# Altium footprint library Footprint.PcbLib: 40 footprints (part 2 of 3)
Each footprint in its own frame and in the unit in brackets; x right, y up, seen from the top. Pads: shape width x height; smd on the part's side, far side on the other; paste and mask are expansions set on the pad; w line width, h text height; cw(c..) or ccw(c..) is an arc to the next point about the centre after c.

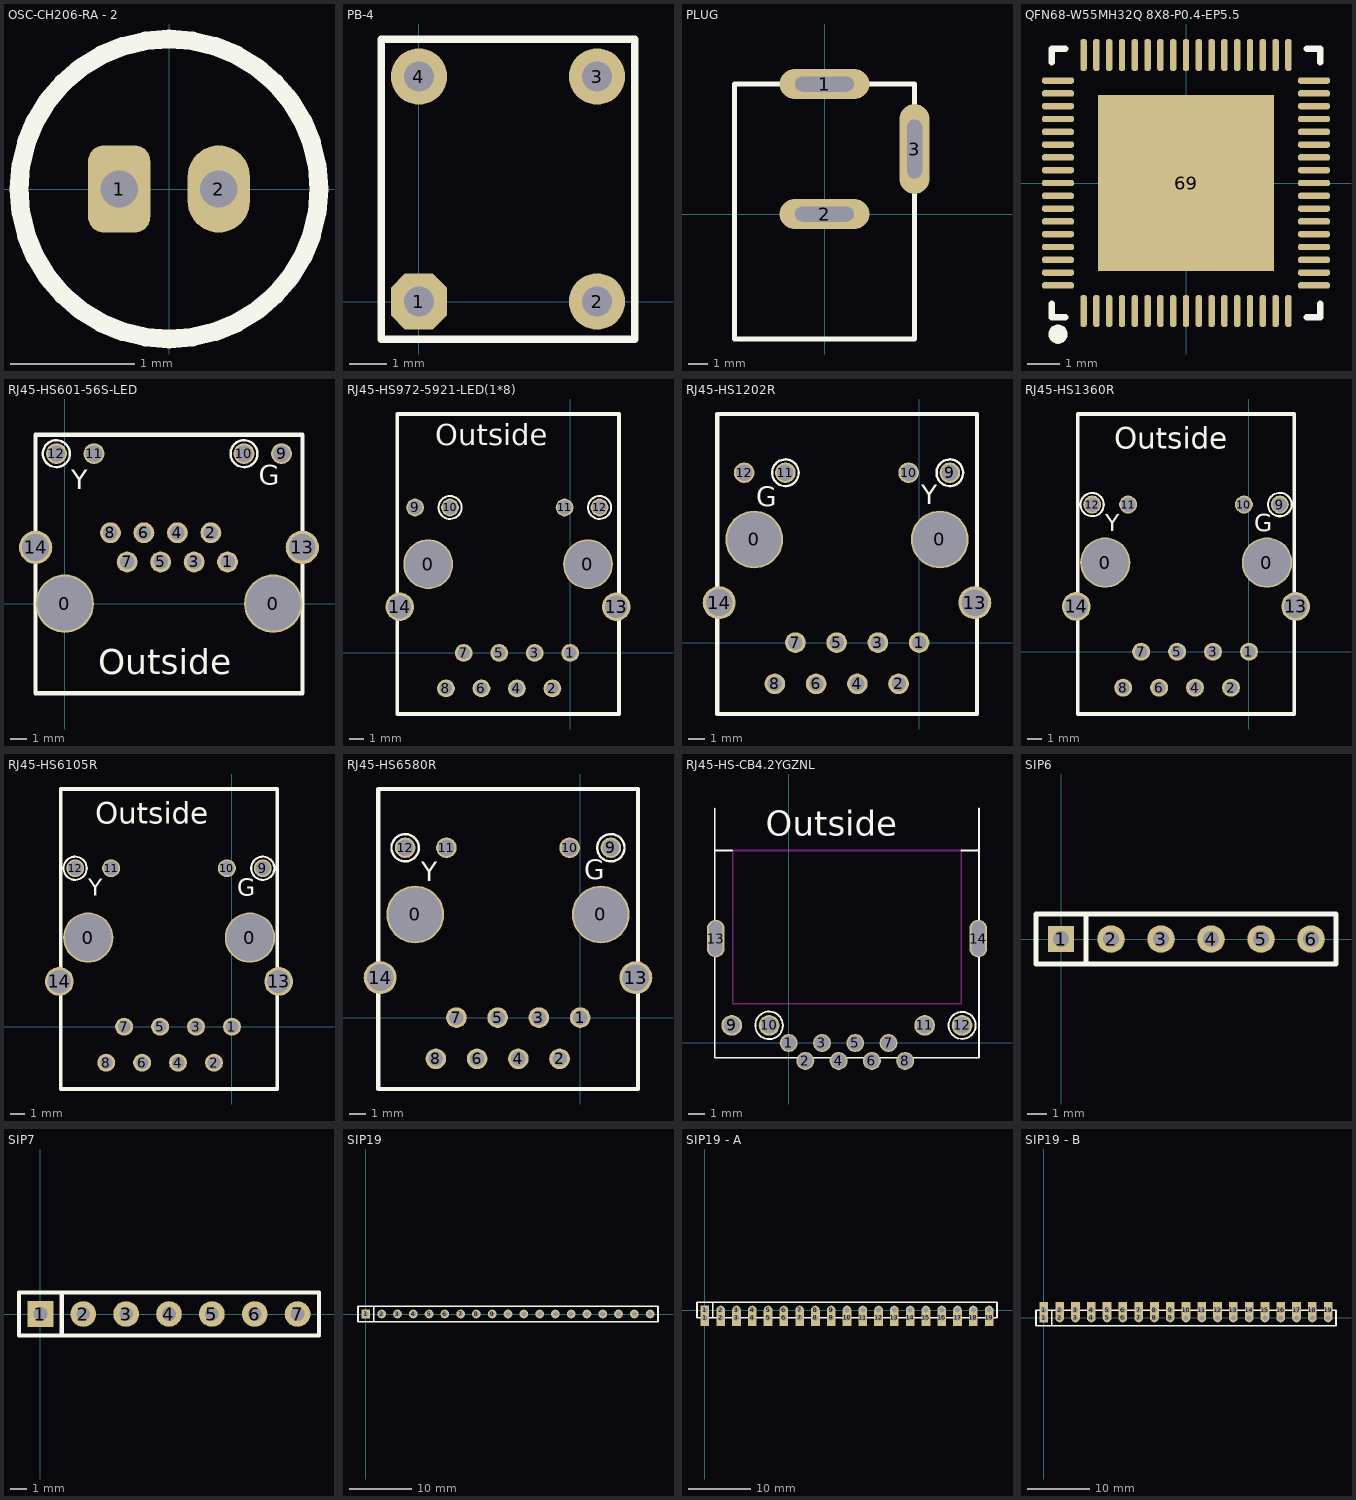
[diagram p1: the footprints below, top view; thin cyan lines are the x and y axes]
## OSC-CH206-RA - 2 [mm]
height 3.9
pads (2):
  rrect50% 0.5x0.7 hole 0.3: 1(-0.4,0)
  oval 0.5x0.7 hole 0.3: 2(0.4,0)
Top Overlay:
  circle w0.15: c0,0 r1.205

## PB-4 [mil]
height 21.65
pads (4):
  oct 60x60 hole 32: 1(0,0)
  round 60 hole 32: 2(190,0) 3(190,240) 4(0,240)
Top Overlay:
  lines w8: -40,-40 -40,280 230,280 230,-40 -40,-40

## PLUG [mil]
pads (3):
  oval 180x60 hole 30 slot 118.11 at 0 deg: 1(0,260) 2(0,0)
  oval 60x180 hole 30 slot 118.11 at 90 deg: 3(180,130)
Top Overlay:
  lines w10: -180,-250 -180,260 180,260 180,-250 -180,-250

## QFN68-W55MH32Q 8X8-P0.4-EP5.5 [mm]
height 1.45
pads (69):
  rrect80% 0.2x1 smd mask+0.051: 1(-3.2,-4) 2(-2.8,-4) 3(-2.4,-4) 4(-2,-4) 5(-1.6,-4) 6(-1.2,-4) 7(-0.8,-4) 8(-0.4,-4) 9(0,-4) 10(0.4,-4) 11(0.8,-4) 12(1.2,-4) 13(1.6,-4) 14(2,-4) 15(2.4,-4) 16(2.8,-4) 17(3.2,-4) 35(3.2,4) 36(2.8,4) 37(2.4,4) 38(2,4) 39(1.6,4) 40(1.2,4) 41(0.8,4) 42(0.4,4) 43(0,4) 44(-0.4,4) 45(-0.8,4) 46(-1.2,4) 47(-1.6,4) 48(-2,4) 49(-2.4,4) 50(-2.8,4) 51(-3.2,4)
  rrect80% 1x0.2 smd mask+0.051: 18(4,-3.2) 19(4,-2.8) 20(4,-2.4) 21(4,-2) 22(4,-1.6) 23(4,-1.2) 24(4,-0.8) 25(4,-0.4) 26(4,0) 27(4,0.4) 28(4,0.8) 29(4,1.2) 30(4,1.6) 31(4,2) 32(4,2.4) 33(4,2.8) 34(4,3.2) 52(-4,3.2) 53(-4,2.8) 54(-4,2.4) 55(-4,2) 56(-4,1.6) 57(-4,1.2) 58(-4,0.8) 59(-4,0.4) 60(-4,0) 61(-4,-0.4) 62(-4,-0.8) 63(-4,-1.2) 64(-4,-1.6) 65(-4,-2) 66(-4,-2.4) 67(-4,-2.8) 68(-4,-3.2)
  rect 5.5x5.5 smd paste-100 mask+0.051: 69(0,0)
Top Overlay:
  lines w0.2: -4.2,-3.775 -4.2,-4.2 -3.775,-4.2 ; -4.2,3.775 -4.2,4.2 -3.775,4.2 ; 3.775,-4.2 4.2,-4.2 4.2,-3.775 ; 3.775,4.2 4.2,4.2 4.2,3.775
  lines w0.3: -4,-4.575 ccw(c-3.999,-4.725) -3.999,-4.875 ccw(c-3.999,-4.725) -3.998,-4.575
3D body: height 1.05, standoff 0, extent -7.999,-7.999 8.001,8.001

## RJ45-HS601-56S-LED [mm]
height 13.2
pads (16):
  round 3.556 hole 3.302: 0(0,0) 0(12.7,0)
  round 1.27 hole 0.889: 1(9.92,2.54) 2(8.9,4.32) 3(7.88,2.54) 4(6.86,4.32) 5(5.84,2.54) 6(4.82,4.32) 7(3.8,2.54) 8(2.78,4.32)
  round 1.27 hole 1.016: 9(13.21,9.14) 10(10.92,9.14) 11(1.78,9.14) 12(-0.51,9.14)
  round 2.032 hole 1.626: 13(14.475,3.43)
  round 2.032 hole 1.651: 14(-1.775,3.43)
Top Overlay:
  circle w0.15: c10.92,9.14 r0.82
  circle w0.15: c-0.514,9.14 r0.82
  lines w0.254: -1.78,-5.46 -1.78,10.29 14.48,10.29 14.48,-5.46 -1.78,-5.46
  text "Outside" at 2.032,-4.318 h1.52
  text "G" at 11.811,7.239 h1.2
  text "Y" at 0.381,6.985 h1.2

## RJ45-HS972-5921-LED(1*8) [mil]
height 537.8
pads (16):
  round 140 hole 130: 0(-400,250) 0(50,250)
  round 50 hole 35: 1(0,0) 2(-50,-100) 3(-100,0) 4(-150,-100) 5(-200,0) 6(-250,-100) 7(-300,0) 8(-350,-100)
  round 50 hole 40: 9(-437.01,409.84) 10(-338.58,409.84) 11(-15.75,409.84) 12(82.68,409.84)
  round 80 hole 64: 13(129.92,129.92)
  round 80 hole 65: 14(-480.31,129.92)
Top Overlay:
  circle w5.91: c82.68,409.84 r32.28
  circle w5.91: c-338.58,409.84 r32.28
  lines w10: -487.6,-172.05 137.6,-172.05 ; -487.6,-171.26 -487.6,673.23 137.6,673.23 137.6,-171.26
  text "Outside" at -380,585 h60

## RJ45-HS1202R [mil]
height 633.46
pads (16):
  round 140 hole 130: 0(-400,250) 0(50,250)
  round 50 hole 35: 1(0,0) 2(-50,-100) 3(-100,0) 4(-150,-100) 5(-200,0) 6(-250,-100) 7(-300,0) 8(-350,-100)
  round 50 hole 40: 9(74.41,411.81) 10(-25.59,411.81) 11(-324.41,411.81) 12(-424.41,411.81)
  round 80 hole 64: 13(135.04,96.85)
  round 80 hole 65: 14(-485.04,96.85)
Top Overlay:
  circle w5.91: c74.41,411.81 r32.3
  circle w5.91: c-324.41,411.81 r32.28
  lines w10: -489.76,-173.23 -489.76,554.33 140.16,554.33 140.16,-173.23 -489.76,-173.23
  text "Y" at 5,335 h47.24
  text "G" at -395,330 h47.24

## RJ45-HS1360R [mil]
height 537.8
pads (16):
  round 140 hole 130: 0(-400,248.03) 0(50,248.03)
  round 50 hole 35: 1(0,0) 2(-50,-100) 3(-100,0) 4(-150,-100) 5(-200,0) 6(-250,-100) 7(-300,0) 8(-350,-100)
  round 50 hole 40: 9(85.83,409.45) 10(-14.17,409.45) 11(-336.22,409.45) 12(-436.22,409.45)
  round 80 hole 64: 13(129.92,125.98)
  round 80 hole 65: 14(-480.31,125.98)
Top Overlay:
  circle w5.91: c85.83,409.45 r32.68
  circle w5.91: c-436.22,409.45 r32.28
  lines w10: -476.38,-173.23 125.98,-173.23 125.98,661.42 -476.38,661.42 -476.38,-173.23
  text "G" at 15,335 h47.24
  text "Y" at -400,335 h47.24
  text "Outside" at -375,565 h60

## RJ45-HS6105R [mil]
height 537.8
pads (16):
  round 140 hole 130: 0(-400,248.03) 0(50,248.03)
  round 50 hole 35: 1(0,0) 2(-50,-100) 3(-100,0) 4(-150,-100) 5(-200,0) 6(-250,-100) 7(-300,0) 8(-350,-100)
  round 50 hole 40: 9(85.83,440.94) 10(-14.17,440.94) 11(-336.22,440.94) 12(-436.22,440.94)
  round 80 hole 64: 13(129.92,125.98)
  round 80 hole 65: 14(-480.31,125.98)
Top Overlay:
  circle w5.91: c-436.22,440.94 r32.28
  circle w5.91: c85.83,440.94 r32.28
  lines w10: -476.38,-173.23 -476.38,661.42 125.98,661.42 125.98,-173.23 -476.38,-173.23
  text "Y" at -400,365 h47.24
  text "G" at 15,365 h47.24
  text "Outside" at -380,565 h60

## RJ45-HS6580R [mil]
height 633.46
pads (16):
  round 140 hole 130: 0(-400,250) 0(50,250)
  round 50 hole 35: 1(0,0) 2(-50,-100) 3(-100,0) 4(-150,-100) 5(-200,0) 6(-250,-100) 7(-300,0) 8(-350,-100)
  round 50 hole 40: 9(74.41,411.81) 10(-25.59,411.81) 11(-324.41,411.81) 12(-424.41,411.81)
  round 80 hole 64: 13(135.04,96.85)
  round 80 hole 65: 14(-485.04,96.85)
Top Overlay:
  circle w5.91: c74.41,411.81 r33.17
  circle w5.91: c-424.41,411.81 r33.17
  lines w10: -489.76,-173.23 140.16,-173.23 140.16,554.33 -489.76,554.33 -489.76,-173.23
  text "Y" at -385,330 h47.24
  text "G" at 10,335 h47.24

## RJ45-HS-CB4.2YGZNL [mm]
height 11.05
pads (14):
  round 1.1 hole 0.9: 1(0,0) 2(1.02,-1.1) 3(2.04,0) 4(3.06,-1.1) 5(4.08,0) 6(5.1,-1.1) 7(6.12,0) 8(7.14,-1.1)
  round 1.27 hole 1: 9(-3.49,1.08) 10(-1.2,1.08) 11(8.34,1.08) 12(10.63,1.08)
  oval 1.1x2.3 hole 0.8 slot 2.1 at 90 deg: 13(-4.47,6.4) 14(11.62,6.4)
Top Overlay:
  circle w0.12: c10.63,1.08 r0.827
  circle w0.12: c-1.2,1.08 r0.846
  lines w0.1: -4.53,11.8 -3.465,11.8 ; -4.53,14.4 -4.53,-0.9 11.67,-0.9 11.67,14.4 ; 10.57,11.8 11.67,11.8
  text "Outside" at -1.397,12.7 h1.52
Keep-Out Layer:
  lines w0.1: -3.43,2.4 10.57,2.4 10.57,11.8 -3.43,11.8 -3.43,2.4

## SIP6 [mil]
height 43.31
pads (6):
  rect 51.06x51.06 hole 32: 1(0,0)
  round 55 hole 32: 2(100,0) 3(200,0) 4(300,0) 5(400,0) 6(500,0)
Top Overlay:
  lines w10: 50,-50 50,50 ; -50,-50 550,-50 550,50 -50,50 -50,-50

## SIP7 [mil]
pads (7):
  rect 60x60 hole 32: 1(0,0)
  round 60 hole 32: 2(100,0) 3(200,0) 4(300,0) 5(400,0) 6(500,0) 7(600,0)
Top Overlay:
  lines w10: 50,-50 50,50 ; 650,-50 -50,-50 -50,50 650,50 650,-45

## SIP19 [mil]
height 43.31
pads (19):
  rect 55x55 hole 32: 1(0,0)
  round 55 hole 32: 2(100,0) 3(200,0) 4(300,0) 5(400,0) 6(500,0) 7(600,0) 8(700,0) 9(800,0) 10(900,0) 11(1000,0) 12(1100,0) 13(1200,0) 14(1300,0) 15(1400,0) 16(1500,0) 17(1600,0) 18(1700,0) 19(1800,0)
Top Overlay:
  lines w10: 50,-50 50,50 ; -50,-50 -50,50 1850,50 1850,-50 -50,-50

## SIP19 - A [mil]
height 43.31
pads (38):
  rect 55x100 hole 32: 1(0,-50) 2(100,-50) 3(200,-50)
  rect 55x55 hole 32: 1(0,0)
  round 55 hole 32: 2(100,0) 3(200,0) 4(300,0) 5(400,0) 6(500,0) 7(600,0) 8(700,0) 9(800,0) 10(900,0) 11(1000,0) 12(1100,0) 13(1200,0) 14(1300,0) 15(1400,0) 16(1500,0) 17(1600,0) 18(1700,0) 19(1800,0)
  rect 55x100 hole 32 unplated: 4(300,-50) 5(400,-50) 6(500,-50) 7(600,-50) 8(700,-50) 9(800,-50) 10(900,-50) 11(1000,-50) 12(1100,-50) 13(1200,-50) 14(1300,-50) 15(1400,-50) 16(1500,-50) 17(1600,-50) 18(1700,-50) 19(1800,-50)
Top Overlay:
  lines w10: 50,-50 50,50 ; -50,-50 -50,50 1850,50 1850,-50 -50,-50

## SIP19 - B [mil]
height 43.31
pads (38):
  rect 55x55 hole 32: 1(0,0)
  rect 55x100 hole 32: 1(0,50) 2(100,50) 3(200,50)
  round 55 hole 32: 2(100,0) 3(200,0) 4(300,0) 5(400,0) 6(500,0) 7(600,0) 8(700,0) 9(800,0) 10(900,0) 11(1000,0) 12(1100,0) 13(1200,0) 14(1300,0) 15(1400,0) 16(1500,0) 17(1600,0) 18(1700,0) 19(1800,0)
  rect 55x100 hole 32 unplated: 4(300,50) 5(400,50) 6(500,50) 7(600,50) 8(700,50) 9(800,50) 10(900,50) 11(1000,50) 12(1100,50) 13(1200,50) 14(1300,50) 15(1400,50) 16(1500,50) 17(1600,50) 18(1700,50) 19(1800,50)
Top Overlay:
  lines w10: 50,-50 50,50 ; -50,-50 1850,-50 1850,50 -50,50 -50,-50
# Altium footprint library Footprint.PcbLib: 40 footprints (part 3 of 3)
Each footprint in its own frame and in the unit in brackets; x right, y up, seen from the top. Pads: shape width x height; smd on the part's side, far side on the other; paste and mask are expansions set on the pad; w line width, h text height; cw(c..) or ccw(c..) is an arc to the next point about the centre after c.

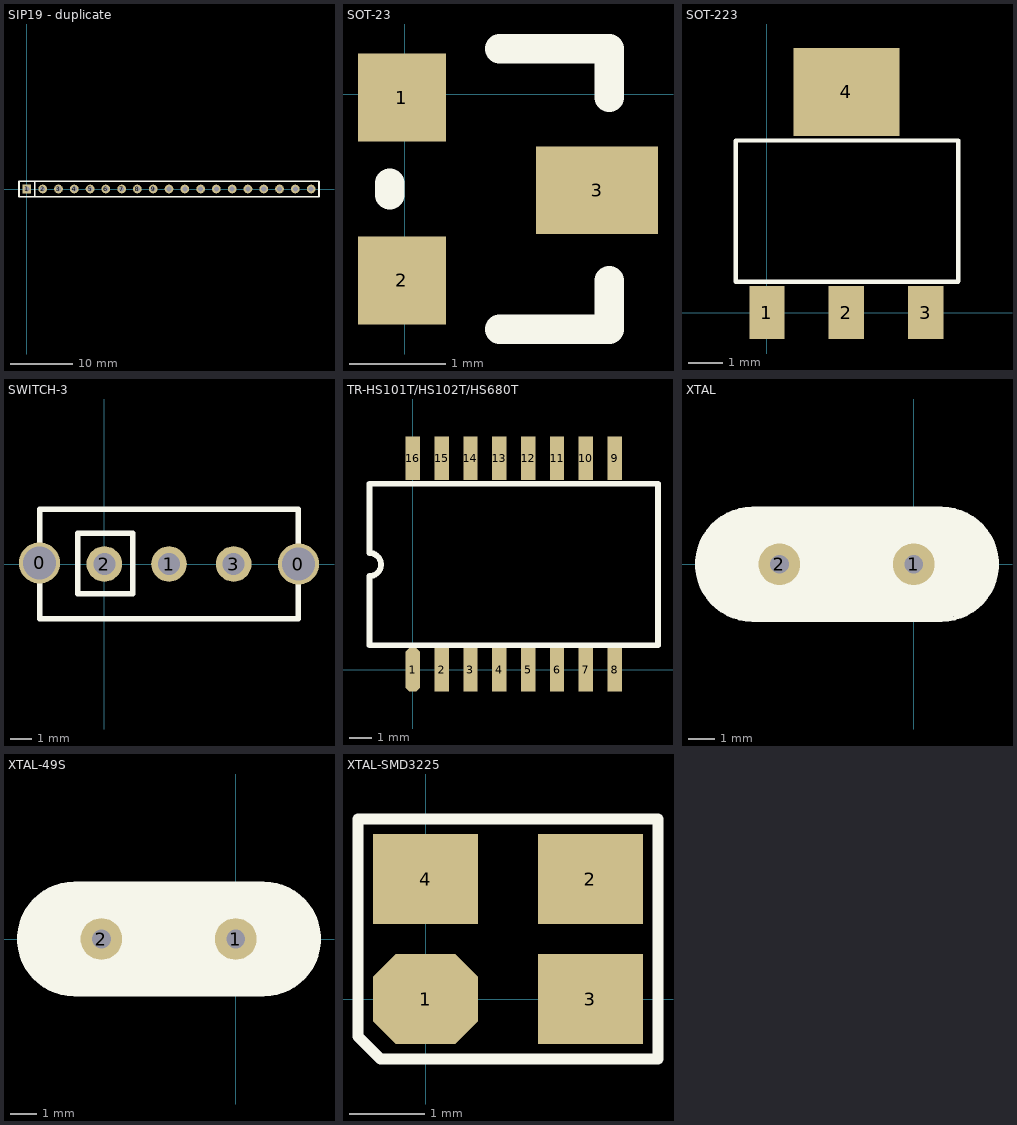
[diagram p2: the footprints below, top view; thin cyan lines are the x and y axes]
## SIP19 - duplicate [mil]
height 43.31
pads (19):
  rect 55x55 hole 32: 1(0,0)
  round 55 hole 32: 2(100,0) 3(200,0) 4(300,0) 5(400,0) 6(500,0) 7(600,0) 8(700,0) 9(800,0) 10(900,0) 11(1000,0) 12(1100,0) 13(1200,0) 14(1300,0) 15(1400,0) 16(1500,0) 17(1600,0) 18(1700,0) 19(1800,0)
Top Overlay:
  lines w10: 50,-50 50,50 ; -50,-50 -50,50 1850,50 1850,-50 -50,-50

## SOT-23 [mil]
height 43.31
pads (3):
  rect 36x36 smd: 1(-1.26,-1.37) 2(-1.26,-76.37)
  rect 50x36 smd: 3(78.74,-39.37)
Top Overlay:
  lines w12: -6.26,-41.37 -6.26,-36.37 ; 38.74,-96.37 83.74,-96.37 83.74,-76.37 ; 38.74,18.63 83.74,18.63 83.74,-1.37

## SOT-223 [mil]
height 43.31
pads (4):
  rect 40x60 smd: 1(0,0) 2(90,0) 3(180,0)
  rect 120x100 smd: 4(90,250)
Top Overlay:
  lines w5: -35.43,35 216.54,35 216.97,35.43 216.97,195 -35,195 -35.43,194.57 -35.43,35

## SWITCH-3 [mil]
height 21.65
pads (5):
  round 75 hole 60: 0(-118,2) 0(354,0)
  round 65 hole 40: 1(118,0) 2(0,0) 3(236,0)
Top Overlay:
  lines w10: -118,-100 -118,100 354,100 354,-100 -118,-100 ; -48,-54 -48,56 52,56 52,-54 -48,-54

## TR-HS101T/HS102T/HS680T [mm]
pads (16):
  oct 0.635x1.905 smd: 1(0,0)
  rect 0.635x1.905 smd: 2(1.27,0) 3(2.54,0) 4(3.81,0) 5(5.08,0) 6(6.35,0) 7(7.62,0) 8(8.89,0) 9(8.89,9.3) 10(7.62,9.3) 11(6.35,9.3) 12(5.08,9.3) 13(3.81,9.3) 14(2.54,9.3) 15(1.27,9.3) 16(0,9.3)
Top Overlay:
  lines w0.254: -1.905,1.07 10.795,1.07 10.795,8.182 -1.905,8.182 -1.905,5.134 cw(c-1.905,4.626) -1.905,4.118 -1.905,1.07

## XTAL [mil]
height 21.65
pads (2):
  round 62 hole 28: 1(0,0) 2(-200,0)
Top Overlay:
  region: -264,74 -280,74 -280,-73 -264,-73
  region: -253,79 -273,79 -273,-78 -253,-78
  region: -240,80 -259,80 -259,-82.67 -240,-82.67
  region: 41.63,83.47 -239.7,83.47 -239.7,-81.88 41.63,-81.88
  region: 58.3,81.79 41.63,81.79 41.63,-81.88 58.3,-81.88
  region: 70,81 58,81 58,-78 70,-78
  region: 79,75 69,75 69,-75 79,-75
  region: 88,71 77,71 77,-70 88,-70
  lines w6: -240,-82.68 cw(c-240,0) -240,82.68 41.34,82.68 cw(c41.34,0) 41.34,-82.68 -240,-82.68
  lines w10: -317,-24 -317,23 -311,29 -311,-37 -308,-40 -308,43 -302,49 -302,-46 -298,-50 -298,54 -294,58 -294,-55 -289,-60 -289,57 -290,58 -290,59 -283,66 -283,-61 ; 88,-60 90,-58 90,63 91,63 97,57 97,-54 96,-55 100,-51 100,49 111,38 106,33 106,-43 112,-37 112,-33 112,30 118,24 118,-25 ; -283,-61 -280,-64 -283,-61

## XTAL-49S [mil]
pads (2):
  round 62 hole 28: 1(0,0) 2(-200,0)
Top Overlay:
  region: -264.02,74 -280.02,74 -280.02,-73 -264.02,-73
  region: -253.02,79 -273.02,79 -273.02,-78 -253.02,-78
  region: -240.02,80 -259.02,80 -259.02,-82.67 -240.02,-82.67
  region: 41.34,82.68 -240,82.68 -240,-82.68 41.34,-82.68
  region: 58,81 41.34,81 41.34,-82.68 58,-82.68
  region: 69.98,81 57.98,81 57.98,-78 69.98,-78
  region: 78.98,75 68.98,75 68.98,-75 78.98,-75
  region: 87.98,71 76.98,71 76.98,-70 87.98,-70
  lines w6: -240,-82.68 cw(c-240,0) -240,82.68 41.34,82.68 cw(c41.34,0) 41.34,-82.68 -240,-82.68
  lines w10: -317,-24 -317,23 -311,29 -311,-37 -308,-40 -308,43 -302,49 -302,-46 -298,-50 -298,54 -294,58 -294,-55 -289,-60 -289,57 -290,58 -290,59 -283,66 -283,-61 ; 88,-60 90,-58 90,63 91,63 97,57 97,-54 96,-55 100,-51 100,49 111,38 106,33 106,-43 112,-37 112,-33 112,30 118,24 118,-25 ; -283,-61 -280,-64 -283,-61

## XTAL-SMD3225 [mm]
pads (4):
  oct 1.4x1.2 smd: 1(0,0)
  rect 1.4x1.2 smd: 2(2.2,1.6) 3(2.2,0) 4(0,1.6)
Top Overlay:
  lines w0.152: -0.9,-0.5 -0.9,2.4 3.1,2.4 3.1,-0.8 -0.6,-0.8 -0.9,-0.5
